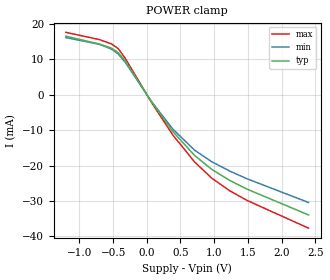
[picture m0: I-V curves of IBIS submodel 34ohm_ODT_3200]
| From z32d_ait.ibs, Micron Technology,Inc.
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| SUBMODEL 34ohm_ODT_3200
[Submodel]   34ohm_ODT_3200
Submodel_type  Dynamic_clamp
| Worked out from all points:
|   POWER clamp passes 1 mA (typ) near -0.03 V on its own axis
[POWER Clamp]
|   Voltage   I(typ)   I(min)   I(max)
-1.2V     16.56mA    16.17mA    17.64mA
-705mV    14.35mA    14.26mA    15.61mA
-525mV    13.18mA    12.92mA    14.39mA
-425mV    11.94mA    11.56mA    13.06mA
-320mV    9.561mA    9.177mA    10.33mA
65mV      -1.857mA   -1.759mA   -2.023mA
385mV     -10.34mA   -9.653mA   -11.31mA
710mV     -17.14mA   -15.65mA   -18.97mA
965mV     -21.08mA   -18.91mA   -23.56mA
1.23V     -24.17mA   -21.53mA   -27.09mA
1.49V     -26.66mA   -23.73mA   -29.85mA
2.4V      -33.93mA   -30.41mA   -37.66mA
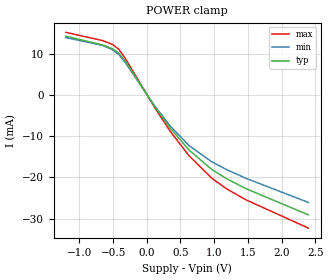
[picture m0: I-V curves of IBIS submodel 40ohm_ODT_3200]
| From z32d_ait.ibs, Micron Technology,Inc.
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| SUBMODEL 40ohm_ODT_3200
[Submodel]   40ohm_ODT_3200
Submodel_type  Dynamic_clamp
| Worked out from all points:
|   POWER clamp passes 1 mA (typ) near -0.04 V on its own axis
[POWER Clamp]
|   Voltage   I(typ)   I(min)   I(max)
-1.2V     14.19mA    13.85mA    15.12mA
-660mV    12.09mA    11.99mA    13.15mA
-510mV    11.17mA    10.94mA    12.21mA
-415mV    10.09mA    9.755mA    11.03mA
-315mV    8.073mA    7.75mA     8.719mA
110mV     -2.682mA   -2.53mA    -2.911mA
350mV     -8.115mA   -7.603mA   -8.885mA
630mV     -13.42mA   -12.33mA   -14.8mA
965mV     -18.07mA   -16.22mA   -20.19mA
1.185V    -20.31mA   -18.11mA   -22.76mA
1.47V     -22.7mA    -20.2mA    -25.41mA
2.4V      -29.08mA   -26.07mA   -32.28mA
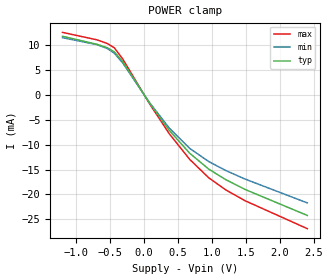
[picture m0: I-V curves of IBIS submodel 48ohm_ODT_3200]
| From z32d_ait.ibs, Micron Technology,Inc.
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| SUBMODEL 48ohm_ODT_3200
[Submodel]   48ohm_ODT_3200
Submodel_type  Dynamic_clamp
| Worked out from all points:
|   POWER clamp passes 1 mA (typ) near -0.05 V on its own axis
[POWER Clamp]
|   Voltage   I(typ)   I(min)   I(max)
-1.2V     11.82mA    11.54mA    12.6mA
-695mV    10.21mA    10.14mA    11.11mA
-540mV    9.502mA    9.341mA    10.36mA
-440mV    8.7mA      8.44mA     9.523mA
-315mV    6.729mA    6.456mA    7.263mA
75mV      -1.529mA   -1.447mA   -1.661mA
370mV     -7.12mA    -6.659mA   -7.793mA
670mV     -11.72mA   -10.74mA   -12.95mA
950mV     -14.91mA   -13.39mA   -16.66mA
1.2V      -17.03mA   -15.19mA   -19.09mA
1.485V    -19.01mA   -16.92mA   -21.28mA
2.4V      -24.24mA   -21.72mA   -26.9mA
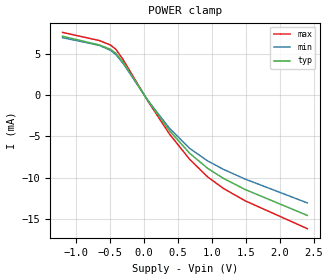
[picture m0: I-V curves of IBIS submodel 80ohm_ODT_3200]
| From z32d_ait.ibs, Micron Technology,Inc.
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| SUBMODEL 80ohm_ODT_3200
[Submodel]   80ohm_ODT_3200
Submodel_type  Dynamic_clamp
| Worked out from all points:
|   POWER clamp passes 1 mA (typ) near -0.08 V on its own axis
[POWER Clamp]
|   Voltage   I(typ)   I(min)   I(max)
-1.2V     7.095mA    6.926mA    7.561mA
-660mV    6.048mA    5.995mA    6.58mA
-495mV    5.522mA    5.398mA    6.039mA
-415mV    5.042mA    4.882mA    5.517mA
-310mV    3.976mA    3.815mA    4.293mA
60mV      -736.4uA   -697.1uA   -799.8uA
375mV     -4.328mA   -4.043mA   -4.733mA
670mV     -7.036mA   -6.445mA   -7.77mA
935mV     -8.863mA   -7.962mA   -9.898mA
1.17V     -10.08mA   -8.994mA   -11.3mA
1.485V    -11.41mA   -10.15mA   -12.77mA
2.4V      -14.54mA   -13.03mA   -16.14mA
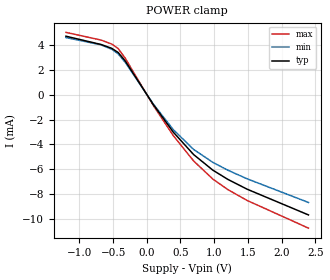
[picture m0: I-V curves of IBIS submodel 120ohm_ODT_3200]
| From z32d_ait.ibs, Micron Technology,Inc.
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| SUBMODEL 120ohm_ODT_3200
[Submodel]   120ohm_ODT_3200
Submodel_type  Dynamic_clamp
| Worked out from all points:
|   POWER clamp passes 1 mA (typ) near -0.12 V on its own axis
[POWER Clamp]
|   Voltage   I(typ)   I(min)   I(max)
-1.2V     4.73mA     4.62mA     5.04mA
-680mV    4.064mA    4.032mA    4.42mA
-520mV    3.751mA    3.677mA    4.098mA
-425mV    3.414mA    3.304mA    3.735mA
-320mV    2.733mA    2.622mA    2.952mA
95mV      -774.3uA   -730.9uA   -842.7uA
395mV     -3.023mA   -2.822mA   -3.307mA
695mV     -4.822mA   -4.409mA   -5.336mA
980mV     -6.079mA   -5.452mA   -6.798mA
1.205V    -6.831mA   -6.089mA   -7.655mA
1.49V     -7.618mA   -6.78mA    -8.528mA
2.4V      -9.695mA   -8.689mA   -10.76mA
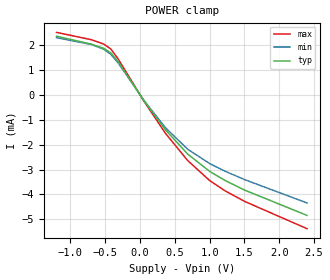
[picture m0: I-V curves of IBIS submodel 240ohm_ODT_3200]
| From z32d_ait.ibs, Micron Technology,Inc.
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| SUBMODEL 240ohm_ODT_3200
[Submodel]   240ohm_ODT_3200
Submodel_type  Dynamic_clamp
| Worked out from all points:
|   POWER clamp passes 1 mA (typ) near -0.23 V on its own axis
[POWER Clamp]
|   Voltage   I(typ)   I(min)   I(max)
-1.2V     2.366mA    2.309mA    2.521mA
-700mV    2.048mA    2.034mA    2.227mA
-520mV    1.877mA    1.84mA     2.05mA
-420mV    1.694mA    1.64mA     1.854mA
-315mV    1.347mA    1.293mA    1.454mA
55mV      -224.3uA   -212.9uA   -244.9uA
365mV     -1.399mA   -1.316mA   -1.541mA
685mV     -2.378mA   -2.183mA   -2.638mA
1V        -3.073mA   -2.758mA   -3.442mA
1.225V    -3.445mA   -3.071mA   -3.862mA
1.505V    -3.829mA   -3.408mA   -4.285mA
2.4V      -4.847mA   -4.345mA   -5.38mA
